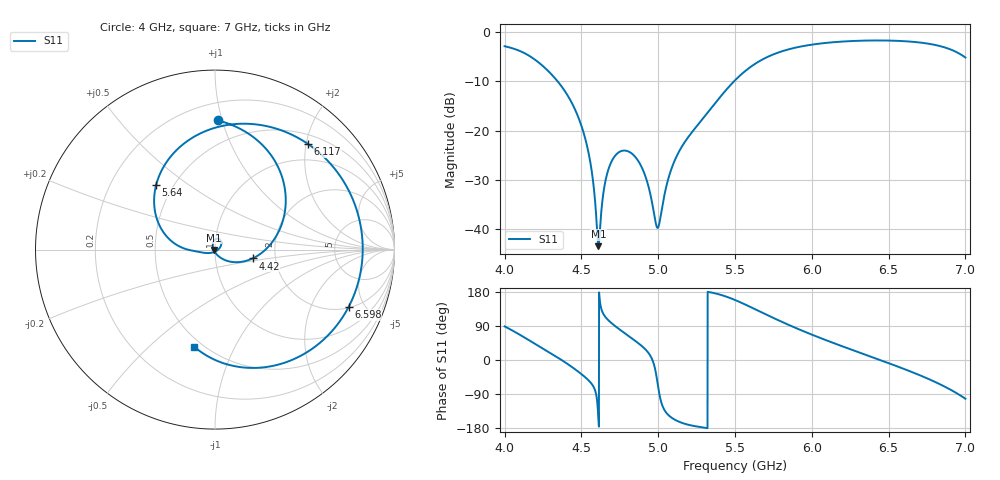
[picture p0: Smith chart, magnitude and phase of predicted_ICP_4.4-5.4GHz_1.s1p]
! ICP-predicted S11, target 4.400-5.400 GHz at -10 dB. Complex ensemble mean (passive and causal);
! its |S11| can differ slightly from the dB-domain mean reported in designs.csv.
!  Air_gap = 1.78mm
!  W_Patch = 11.93mm
!  L_Patch = 18.61mm
!  Sx = 0.34mm
!  Sy = 4.7mm
!  W_Patch1 = 15.35mm
!  WS = 1.36mm
!  Curve_Amp1 = 2.83mm
!  Extra = 5.07mm
# GHz S MA R 50
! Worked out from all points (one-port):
!   3001 points, 4 GHz to 7 GHz, reference 50 ohm
!   lowest |S11| = -43.4 dB at 4.611 GHz (marker M1), VSWR 1.01, Z = 49.4 - j0.272 ohm
!   |S11| at or under -10 dB: 4.346 GHz to 5.493 GHz (1.147 GHz wide, 23.3 % of centre)
!   S11 on the Smith chart (normalised r, x): 4 GHz: 0.32, +0.97; 4.42 GHz: 1.52, -0.16; 5.64 GHz: 0.40, +0.38; 6.117 GHz: 0.67, +2.04; 6.598 GHz: 2.05, -3.82; 7 GHz: 0.45, -0.70
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4  0.7197 88.7
4.189  0.5375 44.9
4.375  0.276 -1.1
4.42  0.2151 -13.3
4.489  0.1259 -33.7
4.541  0.06569 -51.5
4.572  0.03448 -65.9
4.601  0.01048 -103.3
4.611  0.006773 -156.0
4.668  0.03696 108.0
4.75  0.06141 80.1
4.819  0.06022 59.9
4.886  0.0448 39.3
4.931  0.02938 21.6
4.996  0.01037 -61.4
5.066  0.03277 -145.1
5.125  0.05726 -161.0
5.368  0.1879 176.2
5.5  0.3245 158.4
5.64  0.4873 132.3
5.875  0.6852 88.1
6.117  0.7843 48.5
6.25  0.8106 28.5
6.427  0.8232 2.5
6.598  0.8101 -23.2
6.625  0.8052 -27.5
6.836  0.7211 -64.3
7  0.5526 -102.2
